VERSION 5.7 ;
  NOWIREEXTENSIONATPIN ON ;
  DIVIDERCHAR "/" ;
  BUSBITCHARS "[]" ;
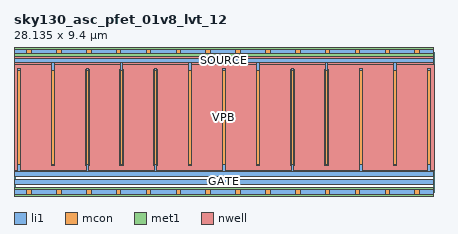
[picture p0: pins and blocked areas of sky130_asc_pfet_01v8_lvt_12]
MACRO sky130_asc_pfet_01v8_lvt_12
  CLASS CORE ;
  FOREIGN sky130_asc_pfet_01v8_lvt_12 ;
  ORIGIN 0.000 0.000 ;
  SIZE 28.135 BY 9.400 ;
  SITE unitasc ;
  PIN GATE
    DIRECTION INOUT ;
    USE SIGNAL ;
    ANTENNAGATEAREA 154.800003 ;
    PORT
      LAYER li1 ;
        RECT 0.010 0.520 28.130 0.820 ;
    END
  END GATE
  PIN SOURCE
    DIRECTION INOUT ;
    USE SIGNAL ;
    ANTENNADIFFAREA 11.223000 ;
    PORT
      LAYER li1 ;
        RECT 0.010 8.650 28.130 8.950 ;
        RECT 2.535 1.755 2.705 8.650 ;
        RECT 7.115 1.755 7.285 8.650 ;
        RECT 11.695 1.755 11.865 8.650 ;
        RECT 16.275 1.755 16.445 8.650 ;
        RECT 20.855 1.755 21.025 8.650 ;
        RECT 25.435 1.755 25.605 8.650 ;
      LAYER mcon ;
        RECT 2.535 1.835 2.705 8.165 ;
        RECT 7.115 1.835 7.285 8.165 ;
        RECT 11.695 1.835 11.865 8.165 ;
        RECT 16.275 1.835 16.445 8.165 ;
        RECT 20.855 1.835 21.025 8.165 ;
        RECT 25.435 1.835 25.605 8.165 ;
      LAYER met1 ;
        RECT 2.505 1.775 2.735 8.225 ;
        RECT 7.085 1.775 7.315 8.225 ;
        RECT 11.665 1.775 11.895 8.225 ;
        RECT 16.245 1.775 16.475 8.225 ;
        RECT 20.825 1.775 21.055 8.225 ;
        RECT 25.405 1.775 25.635 8.225 ;
    END
  END SOURCE
  PIN DRAIN
    DIRECTION INOUT ;
    USE SIGNAL ;
    ANTENNADIFFAREA 13.093500 ;
    PORT
      LAYER li1 ;
        RECT 0.245 1.350 0.415 8.245 ;
        RECT 4.825 1.350 4.995 8.245 ;
        RECT 9.405 1.350 9.575 8.245 ;
        RECT 13.985 1.350 14.155 8.245 ;
        RECT 18.565 1.350 18.735 8.245 ;
        RECT 23.145 1.350 23.315 8.245 ;
        RECT 27.725 1.350 27.895 8.245 ;
        RECT 0.010 1.050 28.130 1.350 ;
      LAYER mcon ;
        RECT 0.245 1.835 0.415 8.165 ;
        RECT 4.825 1.835 4.995 8.165 ;
        RECT 9.405 1.835 9.575 8.165 ;
        RECT 13.985 1.835 14.155 8.165 ;
        RECT 18.565 1.835 18.735 8.165 ;
        RECT 23.145 1.835 23.315 8.165 ;
        RECT 27.725 1.835 27.895 8.165 ;
      LAYER met1 ;
        RECT 0.215 1.775 0.445 8.225 ;
        RECT 4.795 1.775 5.025 8.225 ;
        RECT 9.375 1.775 9.605 8.225 ;
        RECT 13.955 1.775 14.185 8.225 ;
        RECT 18.535 1.775 18.765 8.225 ;
        RECT 23.115 1.775 23.345 8.225 ;
        RECT 27.695 1.775 27.925 8.225 ;
    END
  END DRAIN
  PIN VPB
    DIRECTION INOUT ;
    USE POWER ;
    PORT
      LAYER nwell ;
        RECT 0.010 8.535 28.130 9.700 ;
        RECT 0.005 1.465 28.135 8.535 ;
    END
  END VPB
  PIN VPWR
    DIRECTION INOUT ;
    USE POWER ;
    PORT
      LAYER li1 ;
        RECT 0.010 9.250 28.130 9.550 ;
      LAYER mcon ;
        RECT 0.860 9.250 1.160 9.550 ;
        RECT 2.860 9.250 3.160 9.550 ;
        RECT 4.860 9.250 5.160 9.550 ;
        RECT 6.860 9.250 7.160 9.550 ;
        RECT 8.860 9.250 9.160 9.550 ;
        RECT 10.860 9.250 11.160 9.550 ;
        RECT 12.860 9.250 13.160 9.550 ;
        RECT 14.860 9.250 15.160 9.550 ;
        RECT 16.860 9.250 17.160 9.550 ;
        RECT 18.860 9.250 19.160 9.550 ;
        RECT 20.860 9.250 21.160 9.550 ;
        RECT 22.860 9.250 23.160 9.550 ;
        RECT 24.860 9.250 25.160 9.550 ;
        RECT 26.860 9.250 27.160 9.550 ;
      LAYER met1 ;
        RECT 0.010 9.100 28.130 9.700 ;
    END
  END VPWR
  PIN VGND
    DIRECTION INOUT ;
    USE GROUND ;
    PORT
      LAYER li1 ;
        RECT 0.010 -0.150 28.130 0.150 ;
      LAYER mcon ;
        RECT 0.860 -0.150 1.160 0.150 ;
        RECT 2.860 -0.150 3.160 0.150 ;
        RECT 4.860 -0.150 5.160 0.150 ;
        RECT 6.860 -0.150 7.160 0.150 ;
        RECT 8.860 -0.150 9.160 0.150 ;
        RECT 10.860 -0.150 11.160 0.150 ;
        RECT 12.860 -0.150 13.160 0.150 ;
        RECT 14.860 -0.150 15.160 0.150 ;
        RECT 16.860 -0.150 17.160 0.150 ;
        RECT 18.860 -0.150 19.160 0.150 ;
        RECT 20.860 -0.150 21.160 0.150 ;
        RECT 22.860 -0.150 23.160 0.150 ;
        RECT 24.860 -0.150 25.160 0.150 ;
        RECT 26.860 -0.150 27.160 0.150 ;
      LAYER met1 ;
        RECT 0.010 -0.300 28.130 0.300 ;
    END
  END VGND
END sky130_asc_pfet_01v8_lvt_12
END LIBRARY

